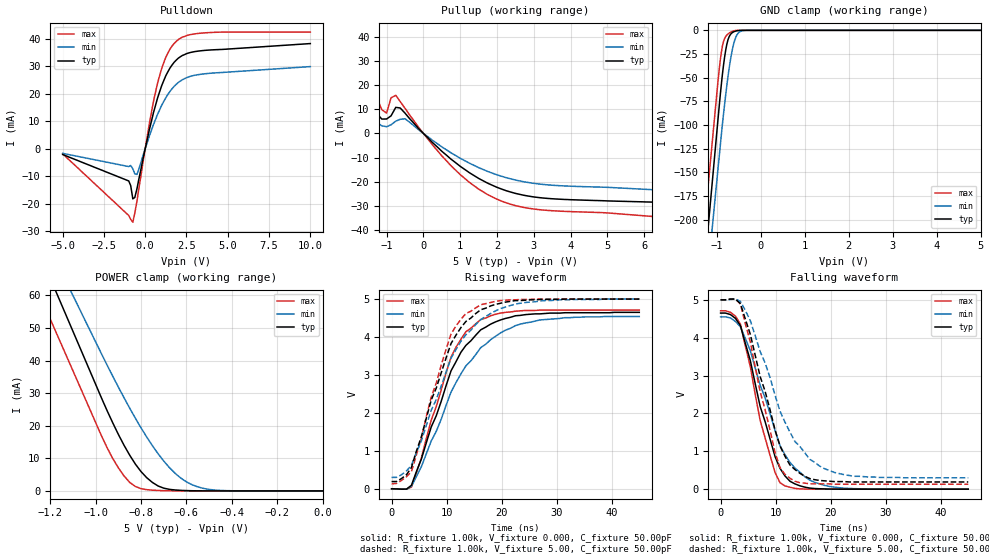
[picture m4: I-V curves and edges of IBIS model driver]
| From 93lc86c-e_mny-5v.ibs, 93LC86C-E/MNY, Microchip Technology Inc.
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|   Model driver
[Model]   driver
Model_type   3-state
Vmeas = 2.5
C_comp   5.00pF   5.00pF   5.00pF
[Temperature Range]   25.00   125.00   -40.00
[Voltage Range]   5.00V   2.50V   5.50V
[Pullup Reference]   5.00V   5.00V   5.00V
[POWER Clamp Reference]   5.00V   5.00V   5.00V
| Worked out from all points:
|   slope of the pulldown table from 0 to 0.75 V, typ, clamps not added: 40.7 ohm
|   slope of the pullup table from 0 to 0.75 V, typ, clamps not added: 70.6 ohm
|   GND clamp passes 1 mA (typ) near -0.59 V on its own axis
|   POWER clamp passes 1 mA (typ) near -0.71 V on its own axis
|   rising waveform, R_fixture 1.00k, V_fixture 0.000, C_fixture 50.00pF: 20-80 % time 7.49ns typ, 9.49ns min, 6.23ns max; typ from 0 V to 4.65 V
|   rising waveform, R_fixture 1.00k, V_fixture 5.00, C_fixture 50.00pF: 20-80 % time 6.77ns typ, 8.16ns min, 5.74ns max; typ from 0.19 V to 5 V
|   falling waveform, R_fixture 1.00k, V_fixture 0.000, C_fixture 50.00pF: 20-80 % time 5ns typ, 6.26ns min, 4.38ns max; typ from 4.65 V to 0 V
|   falling waveform, R_fixture 1.00k, V_fixture 5.00, C_fixture 50.00pF: 20-80 % time 5.29ns typ, 7.36ns min, 4.55ns max; typ from 5 V to 0.19 V
[GND_clamp]
| voltage   I(typ)   I(min)   I(max)
-5V       -2.144A    -2.061A    -2.033A
-1.4V     -309.4mA   -347.6mA   -261.8mA
-1.25V    -233mA     -276.2mA   -188mA
-1.1V     -156.6mA   -204.8mA   -114.2mA
-975mV    -92.86mA   -145.3mA   -52.65mA
-900mV    -56.69mA   -110mA     -23mA
-850mV    -36.25mA   -87.81mA   -11.57mA
-775mV    -14.57mA   -57.94mA   -4.945mA
-650mV    -2.399mA   -20.18mA   -1.096mA
-550mV    -525.5uA   -5.176mA   -103.4uA
-375mV    -2.846uA   -171.2uA   -47.76nA
5V        10pA       10.71nA    10pA
[POWER_clamp]
| voltage   I(typ)   I(min)   I(max)
-5V       683.9mA    615.3mA    656.2mA
-1.25V    73.39mA    81.31mA    60.67mA
-1.175V   61.18mA    70.63mA    48.76mA
-1.15V    57.11mA    67.07mA    44.79mA
-1.1V     48.97mA    59.95mA    36.85mA
-975mV    28.62mA    42.15mA    17mA
-900mV    17.34mA    31.86mA    7.07mA
-825mV    8.218mA    22.29mA    1.355mA
-750mV    2.602mA    13.87mA    229.3uA
-625mV    173.4uA    3.939mA    11.21uA
-525mV    15.81uA    771.6uA    193.4nA
0V        10pA       4.313nA    10pA
[Pulldown]
| voltage   I(typ)   I(min)   I(max)
-5V       -2.134mA   -1.715mA   -1.88mA
-1V       -11.73mA   -6.515mA   -24.28mA
-880mV    -13.41mA   -6.135mA   -25.7mA
-750mV    -18.26mA   -7.325mA   -26.73mA
-630mV    -17.74mA   -9.205mA   -23.4mA
-500mV    -14.57mA   -9.368mA   -19.07mA
250mV     6.874mA    4.572mA    9.108mA
750mV     18.45mA    12.51mA    23.85mA
1.25V     26.53mA    18.55mA    33.22mA
1.75V     31.38mA    22.64mA    38.23mA
3.25V     35.48mA    26.93mA    41.89mA
10V       38.19mA    29.82mA    42.36mA
[Pullup]
| voltage   I(typ)   I(min)   I(max)
-5V       73.95mA    44.93mA    149.2mA
-3.31V    44.25mA    26.7mA     88.42mA
-2.13V    23.35mA    13.88mA    45.67mA
-1.13V    5.957mA    3.157mA    9.823mA
-1V       5.987mA    2.797mA    8.453mA
-880mV    7.277mA    3.577mA    14.71mA
-750mV    10.81mA    5.107mA    15.79mA
-500mV    8.415mA    6.084mA    10.43mA
750mV     -10.63mA   -8.019mA   -13.36mA
2.25V     -23.7mA    -18.3mA    -28.72mA
3.75V     -27.24mA   -21.65mA   -32.18mA
10V       -29.91mA   -26.29mA   -38.88mA
[Ramp]
| variable   typ   min   max
dV/dt_r   2.79/0.51n   2.73/0.62n   2.83/0.62n
dV/dt_f   2.88/0.54n   2.82/0.72n   2.92/0.49n
R_load = 1.00k
[Rising Waveform]
R_fixture = 1.00k
V_fixture = 0.000
C_fixture = 50.00pF
| time   V(typ)   V(min)   V(max)
0s        730pV      16.84nV    520pV
3.6ns     90.81mV    63.74mV    41.64mV
5.4ns     780mV      580mV      810mV
8.1ns     1.92V      1.51V      2.16V
10.8ns    3.11V      2.55V      3.47V
13.5ns    3.78V      3.24V      4.14V
16.2ns    4.19V      3.72V      4.46V
20.7ns    4.49V      4.18V      4.65V
27ns      4.61V      4.45V      4.71V
45ns      4.65V      4.54V      4.71V
[Rising Waveform]
R_fixture = 1.00k
V_fixture = 5.00
C_fixture = 50.00pF
| time   V(typ)   V(min)   V(max)
0s        190mV      300mV      130mV
1.8ns     270mV      370mV      220mV
3.6ns     560mV      620mV      450mV
5.4ns     1.37V      1.26V      1.33V
7.2ns     2.34V      2.07V      2.42V
10.8ns    3.83V      3.44V      4.08V
13.5ns    4.41V      4.06V      4.62V
16.2ns    4.72V      4.46V      4.85V
22.5ns    4.96V      4.87V      4.98V
45ns      5V         5V         5V
[Falling Waveform]
R_fixture = 1.00k
V_fixture = 0.000
C_fixture = 50.00pF
| time   V(typ)   V(min)   V(max)
0s        4.65V      4.55V      4.71V
1.8ns     4.61V      4.52V      4.67V
3.6ns     4.32V      4.29V      4.36V
5.4ns     3.4V       3.66V      3.24V
7.2ns     2.18V      2.74V      1.81V
9.9ns     860mV      1.55V      440mV
10.8ns    550mV      1.15V      170mV
13.5ns    140mV      560mV      20.69mV
18.9ns    6.12mV     100mV      47.37uV
45ns      -2.97nV    7.89uV     81.8nV
[Falling Waveform]
R_fixture = 1.00k
V_fixture = 5.00
C_fixture = 50.00pF
| time   V(typ)   V(min)   V(max)
0s        5V         5V         5V
3.6ns     4.9V       4.96V      4.89V
5.4ns     4.09V      4.45V      3.89V
7.2ns     2.97V      3.63V      2.57V
9.9ns     1.56V      2.48V      970mV
10.8ns    1.14V      2.06V      570mV
12.6ns    640mV      1.51V      290mV
16.2ns    280mV      790mV      140mV
20.7ns    200mV      440mV      130mV
45ns      190mV      300mV      130mV
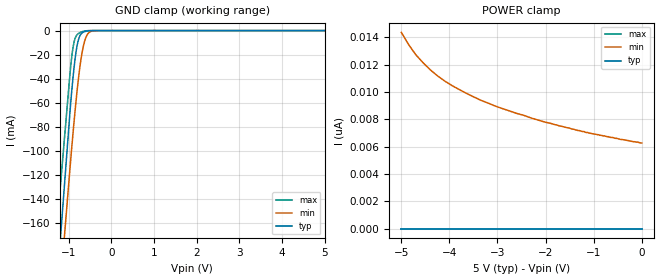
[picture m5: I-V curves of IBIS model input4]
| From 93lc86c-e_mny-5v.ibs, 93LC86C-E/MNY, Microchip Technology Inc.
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|   Model input4
[Model]   input4
Model_type   Input
Vinl = 0.8
Vinh = 2.0
C_comp   5.00pF   5.00pF   5.00pF
[Temperature Range]   25.00   125.00   -40.00
[Voltage Range]   5.00V   2.50V   5.50V
[Pullup Reference]   5.00V   5.00V   5.00V
[POWER Clamp Reference]   5.00V   5.00V   5.00V
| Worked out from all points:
|   GND clamp passes 1 mA (typ) near -0.64 V on its own axis
[GND_clamp]
| voltage   I(typ)   I(min)   I(max)
-5V       -1.955A    -1.856A    -1.708A
-1.4V     -269.2mA   -300.5mA   -214.4mA
-1.25V    -199mA     -235.7mA   -152.1mA
-1.1V     -128.7mA   -170.9mA   -89.91mA
-975mV    -70.14mA   -116.9mA   -38.06mA
-900mV    -39.61mA   -85.91mA   -14.46mA
-825mV    -17.08mA   -57.57mA   -4.495mA
-725mV    -3.555mA   -27mA      -1.499mA
-675mV    -1.67mA    -16.22mA   -806.2uA
-600mV    -588.2uA   -6.001mA   -207.5uA
-425mV    -10.15uA   -245.9uA   -3.271uA
5V        -111.8nA   -71.21nA   -148.1nA
[POWER_clamp]
| voltage   I(typ)   I(min)   I(max)
-5V       10pA       14.36nA    10pA
-4.85V    10pA       13.48nA    10pA
-4.7V     10pA       12.73nA    10pA
-4.55V    10pA       12.15nA    10pA
-4.4V     10pA       11.63nA    10pA
-4.25V    10pA       11.19nA    10pA
-3.95V    10pA       10.48nA    10pA
-3.35V    10pA       9.401nA    10pA
-2.9V     10pA       8.79nA     10pA
-2V       10pA       7.788nA    10pA
-1.15V    10pA       7.04nA     10pA
0V        10pA       6.27nA     10pA
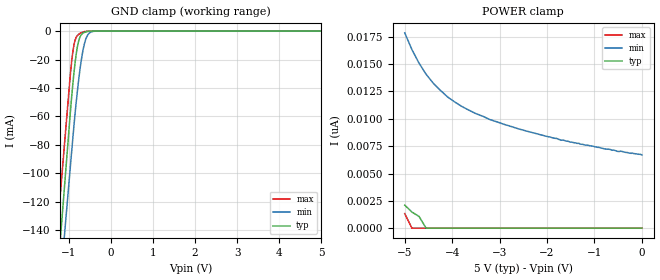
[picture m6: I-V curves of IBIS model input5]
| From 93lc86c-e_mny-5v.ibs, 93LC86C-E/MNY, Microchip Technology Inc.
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|   Model input5
[Model]   input5
Model_type   Input
Vinl = 0.8
Vinh = 2.0
C_comp   5.00pF   5.00pF   5.00pF
[Temperature Range]   25.00   125.00   -40.00
[Voltage Range]   5.00V   2.50V   5.50V
[Pullup Reference]   5.00V   5.00V   5.00V
[POWER Clamp Reference]   5.00V   5.00V   5.00V
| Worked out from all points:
|   GND clamp passes 1 mA (typ) near -0.64 V on its own axis
[GND_clamp]
| voltage   I(typ)   I(min)   I(max)
-5V       -1.573A    -1.48A     -1.46A
-1.4V     -220.7mA   -244.9mA   -184.6mA
-1.25V    -164.3mA   -193.4mA   -131.5mA
-1.1V     -108mA     -141.9mA   -78.31mA
-975mV    -61.05mA   -99.02mA   -34.01mA
-925mV    -43.42mA   -81.84mA   -19.04mA
-875mV    -28.21mA   -65.07mA   -9.154mA
-800mV    -11.49mA   -42.94mA   -3.232mA
-700mV    -2.412mA   -19.67mA   -1.104mA
-575mV    -395.6uA   -4.004mA   -105.6uA
-400mV    -3.298uA   -144.5uA   -74.14nA
5V        10pA       4.974nA    10pA
[POWER_clamp]
| voltage   I(typ)   I(min)   I(max)
-5V       2.109nA    17.84nA    1.336nA
-4.85V    1.48nA     16.32nA    10pA
-4.7V     1.086nA    15.08nA    10pA
-4.55V    10pA       14.06nA    10pA
-4.4V     10pA       13.25nA    10pA
-4.1V     10pA       12nA       10pA
-3.65V    10pA       10.79nA    10pA
-3.2V     10pA       9.918nA    10pA
-2.9V     10pA       9.483nA    10pA
-1.7V     10pA       8.039nA    10pA
-525mV    10pA       7.032nA    10pA
0V        10pA       6.699nA    10pA
